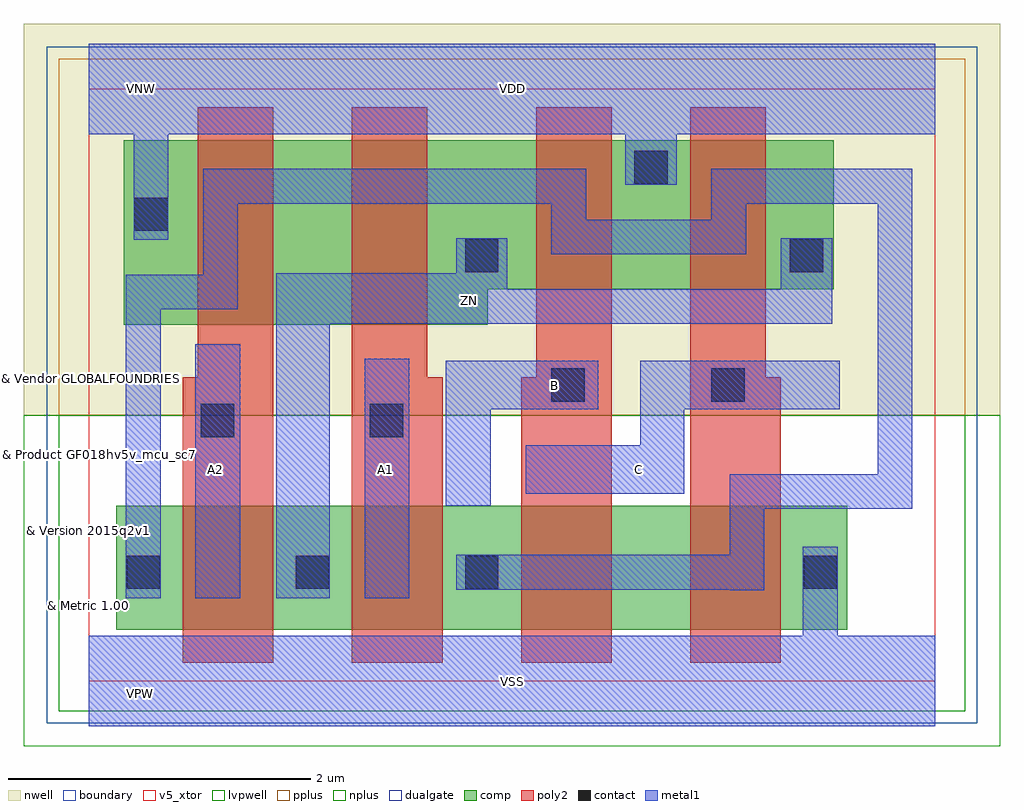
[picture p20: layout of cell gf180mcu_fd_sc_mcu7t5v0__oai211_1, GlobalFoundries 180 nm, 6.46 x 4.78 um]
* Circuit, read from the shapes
.subckt gf180mcu_fd_sc_mcu7t5v0__oai211_1 A1 A2 B C VDD VNW VSS ZN
XM1 ZN A2 n1 VSUBS nfet_05v0 w=0.82u l=0.6u
XM2 n1 A1 ZN VSUBS nfet_05v0 w=0.82u l=0.6u
XM3 n2 B n1 VSUBS nfet_05v0 w=0.82u l=0.6u
XM4 VSS C n2 VSUBS nfet_05v0 w=0.82u l=0.6u
XM5 n3 A2 VDD VNW pfet_05v0 w=1.22u l=0.5u
XM6 ZN A1 n3 VNW pfet_05v0 w=1.22u l=0.5u
XM7 VDD B ZN VNW pfet_05v0 w=0.985u l=0.5u
XM8 ZN C VDD VNW pfet_05v0 w=0.985u l=0.5u
.ends

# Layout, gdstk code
import gdstk
lib = gdstk.Library(unit=1e-6, precision=1e-09)
def R(c, l, rs):  # rectangles x0, y0, x1, y1
    for r in rs: c.add(gdstk.rectangle(r[:2], r[2:], *l))
def A(c, l, x, y, w, h, nx, ny, dx, dy):  # array of equal rectangles
    R(c, l, [(x+i*dx, y+j*dy, x+i*dx+w, y+j*dy+h) for i in range(nx) for j in range(ny)])
def P(c, l, *ps):  # polygons
    for p in ps: c.add(gdstk.Polygon(p, *l))
boundary = (0, 0)
nwell = (21, 0)
comp = (22, 0)
poly2 = (30, 0)
pplus = (31, 0)
nplus = (32, 0)
contact = (33, 0)
metal1 = (34, 0)
dualgate = (55, 0)
v5_xtor = (112, 1)
lvpwell = (204, 0)

gf180mcu_fd_sc_mcu7t5v0_ = lib.new_cell('gf180mcu_fd_sc_mcu7t5v0__oai211_1')
R(gf180mcu_fd_sc_mcu7t5v0_, boundary, [(0,0,5.6,3.92)])
R(gf180mcu_fd_sc_mcu7t5v0_, nwell, [(-0.43,1.76,6.03,4.35)])
R(gf180mcu_fd_sc_mcu7t5v0_, comp, [(0.18,0.34,5.02,1.16)])
P(gf180mcu_fd_sc_mcu7t5v0_, comp, [(0.23,2.36),(0.23,3.58),(4.93,3.58),(4.93,2.595),(2.64,2.595),(2.64,2.36)])
P(gf180mcu_fd_sc_mcu7t5v0_, poly2, [(0.62,0.12),(0.62,2.01),(0.72,2.01),(0.72,3.8),(1.22,3.8),(1.22,0.12)],
  [(1.74,0.12),(1.74,3.8),(2.24,3.8),(2.24,2.01),(2.34,2.01),(2.34,0.12)],
  [(2.86,0.12),(2.86,2.01),(2.96,2.01),(2.96,3.8),(3.46,3.8),(3.46,0.12)],
  [(3.98,0.12),(3.98,3.8),(4.48,3.8),(4.48,2.01),(4.58,2.01),(4.58,0.12)])
R(gf180mcu_fd_sc_mcu7t5v0_, pplus, [(-0.2,1.76,5.8,4.12)])
R(gf180mcu_fd_sc_mcu7t5v0_, nplus, [(-0.2,-0.2,5.8,1.76)])
A(gf180mcu_fd_sc_mcu7t5v0_, contact, 0.25, 0.61, 0.22, 0.22, 3, 1, 1.12, 0)
R(gf180mcu_fd_sc_mcu7t5v0_, contact, [(4.73,0.61,4.95,0.83), (0.74,1.615,0.96,1.835), (1.86,1.615,2.08,1.835), (3.06,1.85,3.28,2.07), (4.12,1.85,4.34,2.07), (2.49,2.705,2.71,2.925), (4.64,2.705,4.86,2.925), (0.3,2.98,0.52,3.2), (3.61,3.29,3.83,3.51)])
R(gf180mcu_fd_sc_mcu7t5v0_, metal1, [(0.705,0.55,1,2.23), (1.825,0.55,2.12,2.135)])
P(gf180mcu_fd_sc_mcu7t5v0_, metal1, [(2.36,1.16),(2.36,2.12),(3.37,2.12),(3.37,1.8),(2.66,1.8),(2.66,1.16)],
  [(1.24,0.55),(1.24,2.7),(2.43,2.7),(2.43,2.93),(2.77,2.93),(2.77,2.595),(4.58,2.595),(4.58,2.93),(4.92,2.93),(4.92,2.365),(1.595,2.365),(1.595,0.55)],
  [(2.89,1.24),(2.89,1.56),(3.65,1.56),(3.65,2.12),(4.97,2.12),(4.97,1.8),(3.94,1.8),(3.94,1.24)],
  [(0.245,0.55),(0.245,2.69),(0.755,2.69),(0.755,3.39),(3.29,3.39),(3.29,3.055),(4.12,3.055),(4.12,3.39),(5.45,3.39),(5.45,1.14),(4.47,1.14),(4.47,0.6),(4.24,0.6),(4.24,0.605),(2.43,0.605),(2.43,0.835),(4.24,0.835),(4.24,1.37),(5.22,1.37),(5.22,3.16),(4.35,3.16),(4.35,2.825),(3.06,2.825),(3.06,3.16),(0.985,3.16),(0.985,2.46),(0.475,2.46),(0.475,0.55)],
  [(0,-0.3),(0,0.3),(4.725,0.3),(4.725,0.89),(4.955,0.89),(4.955,0.3),(5.6,0.3),(5.6,-0.3)],
  [(0.295,2.92),(0.295,3.62),(0,3.62),(0,4.22),(5.6,4.22),(5.6,3.62),(3.89,3.62),(3.89,3.285),(3.55,3.285),(3.55,3.62),(0.525,3.62),(0.525,2.92)])
R(gf180mcu_fd_sc_mcu7t5v0_, dualgate, [(-0.28,-0.28,5.88,4.2)])
R(gf180mcu_fd_sc_mcu7t5v0_, v5_xtor, [(0,0,5.6,3.92)])
R(gf180mcu_fd_sc_mcu7t5v0_, lvpwell, [(-0.43,-0.43,6.03,1.76)])
gf180mcu_fd_sc_mcu7t5v0_.add(gdstk.Label('B', (3.08,1.96), layer=34, texttype=10))
gf180mcu_fd_sc_mcu7t5v0_.add(gdstk.Label('C', (3.64,1.4), layer=34, texttype=10))
gf180mcu_fd_sc_mcu7t5v0_.add(gdstk.Label('VDD', (2.8,3.92), layer=34, texttype=10))
gf180mcu_fd_sc_mcu7t5v0_.add(gdstk.Label('VSS', (2.8,0), layer=34, texttype=10))
gf180mcu_fd_sc_mcu7t5v0_.add(gdstk.Label('ZN', (2.52,2.52), layer=34, texttype=10))
gf180mcu_fd_sc_mcu7t5v0_.add(gdstk.Label('A1', (1.96,1.4), layer=34, texttype=10))
gf180mcu_fd_sc_mcu7t5v0_.add(gdstk.Label('A2', (0.84,1.4), layer=34, texttype=10))
gf180mcu_fd_sc_mcu7t5v0_.add(gdstk.Label('& Vendor GLOBALFOUNDRIES', (0,2), layer=63, texttype=63))
gf180mcu_fd_sc_mcu7t5v0_.add(gdstk.Label('& Product GF018hv5v_mcu_sc7', (0,1.5), layer=63, texttype=63))
gf180mcu_fd_sc_mcu7t5v0_.add(gdstk.Label('& Version 2015q2v1', (0,1), layer=63, texttype=63))
gf180mcu_fd_sc_mcu7t5v0_.add(gdstk.Label('& Metric 1.00', (0,0.5), layer=63, texttype=63))
gf180mcu_fd_sc_mcu7t5v0_.add(gdstk.Label('VNW', (0.345,3.92), layer=21, texttype=10))
gf180mcu_fd_sc_mcu7t5v0_.add(gdstk.Label('VPW', (0.34,-0.085), layer=204, texttype=10))

lib.write_gds('gf180mcu_fd_sc_mcu7t5v0__oai211_1.gds')
